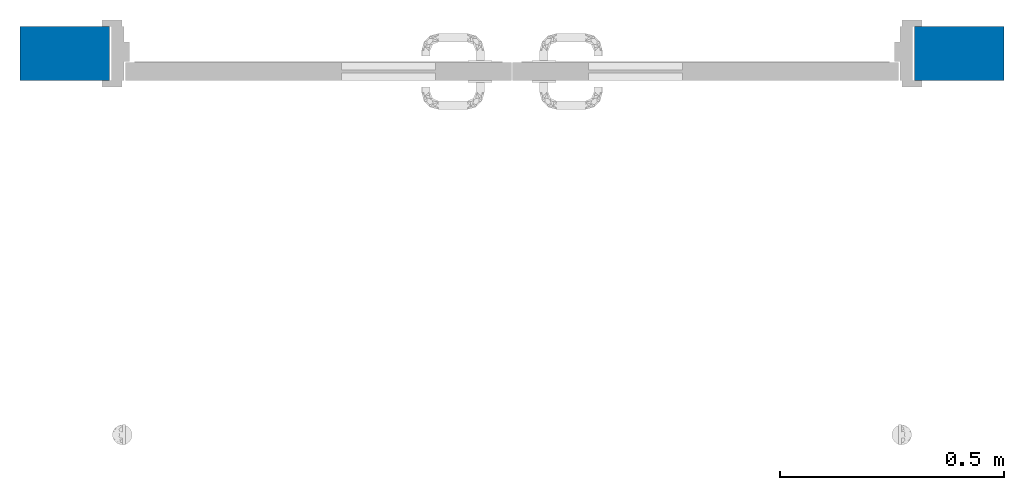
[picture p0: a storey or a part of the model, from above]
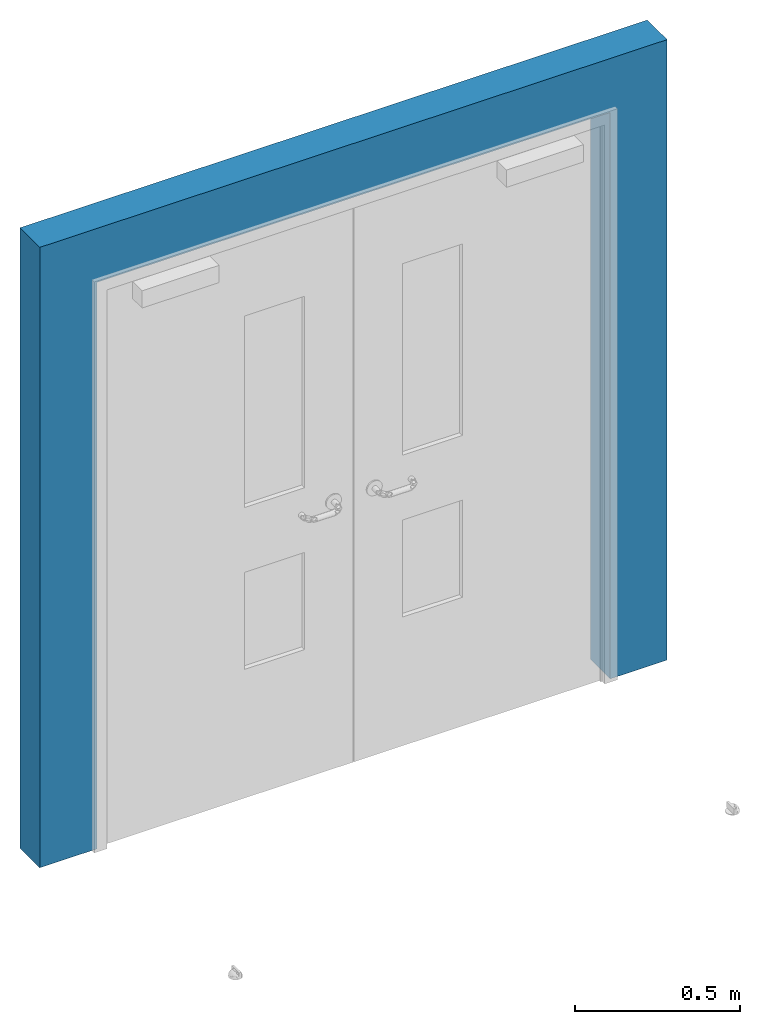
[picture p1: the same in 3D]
Properties of the parts of a building model (IFC2X3)

# File
Description: ViewDefinition [CoordinationView_V2.0]
File name: Project Number
Time: 2014-12-09T12:13:59
Written by: The EXPRESS Data Manager Version 5.01.0100.02.64mod : 6 Jun 2012
Made in: 20130709_2115(x64) - Exporter 3.12.0.0 - Alternate UI 2.12.0.0
Comment: STEP Physical File produced by: The EXPRESS Data Manager Version 5.01.0100.02.64mod : 6 Jun 2012 * Module: EDMstepFileFactory/EDMstandAlone * Creation date: Tue Dec 09 12:13:59 2014 * Host: NCL-PI08 * Database: C:\Users\KovacsG\AppData\Local\Temp\{104F14B4-FB82-4425-A065-D12D6DB6A748}\ifc * Database version: 5507 * Database creation date: Tue Dec 09 12:13:59 2014 * Schema: IFC2X3 * Model: DataRepository.ifc * Model creation date: Tue Dec 09 12:13:59 2014 * Header model: DataRepository.ifc_HeaderModel * Header model creation date: Tue Dec 09 12:13:59 2014 * EDMuser: sdai-user * EDMgroup: sdai-group * License ID and type: 5605 : Permanent license. Expiry date: * EDMstepFileFactory options: 020000

# IfcProject, Project Number
LongName: Project Name; Phase: Project Status

# IfcSite, Default
RefLatitude: 51, 30, 0, 549316; RefLongitude: 0, -7, -34, -450321; RefElevation: 0 mm

# IfcBuildingStorey, Level 0
LongName: Level 0; Elevation: 0 mm

# IfcDoor: 1800x2100mm-NFR, NBS_AssaAbloyLtd_DrsetSym_SelectDoorSix:1800x2100mm-NFR:410865
In: Level 0
Type - ParameterTakesPrecedence: no; Sizeable: no; Material: NBS_Concept, NBS_Glass
OverallHeight: 2100 mm; OverallWidth: 1800 mm
NBS_General - Author: NBS; BIMObjectName: NBS_AssaAbloyLtd_DoorsetSystem_SelectDoorSix_1800x2100mm-NFR; ManufacturerURL: www.assaabloy.co.uk; NBSCertification: www.nationalbimlibrary.com/assa-abloy/assa-abloy-select-door-six; NBSDescription: Doorset system; NBSNote: n/a; NBSOfficeMasterTag: n/a; NBSReference: 25-50-20/120; NBSTypeID: n/a; ProductInformation: n/a; Revision: n/a; Uniclass2: 25-30-20/120; Version: 2
COBie - AccessibilityPerformance: n/a; AssetIdentifier: n/a; AssetType: Fixed; BarCode: n/a; Category: n/a; CodePerformance: n/a; Color: n/a; Constituents: n/a; Description: ASSA ABLOY Double Doorset designed for use in an education or health environment such as a typical corridor application; DurationUnit: year; ExpectedLife: n/a; Features: n/a; Finish: n/a; Grade: n/a; InstallationDate: 1900-12-31T23:59:59; Manufacturer: ASSA ABLOY LTD; Material: n/a; ModelNumber: n/a; ModelReference: ASSA ABLOY Select Door Six; Name: Doorset system; NominalHeight: 2100 mm; NominalLength: 0 mm; NominalWidth: 1800 mm; ReplacementCost: n/a; SerialNumber: n/a; Shape: Rectangle; Size: 1800 x 2100 mm; SustainabilityPerformance: n/a; TagNumber: n/a; WarrantyDescription: n/a; WarrantyDurationLabor: n/a; WarrantyDurationParts: n/a; WarrantyDurationUnit: year; WarrantyGuarantorLabor: n/a; WarrantyGuarantorParts: n/a; WarrantyStartDate: 1900-12-31T23:59:59
Pset_DoorCommon - Reference: n/a; FireRating: Unrated; AcousticRating: 30 dB; SecurityRating: n/a; IsExternal: no; Infiltration: 0 m3/s; ThermalTransmittance: 0 kg/K/s3; HandicapAccessible: no; FireExit: no; SelfClosing: no; SmokeStop: no; HasDrive: no
NBS_Data - AccessoryOptions: ScanFlex Signage (male symbol, female symbol, disabled symbol, fire door keep shut, automatic fire door keep clear); AcousticRatingOptions: 30 dB (40 mm doorset thickness), 35 dB (62 mm doorset thickness); AdditionalHardware: DC500A CAM-motion; AirTransferGrille: no; AirTransferGrilleSize: n/a; AlternativeDoorsetGlazing: n/a; AntiFingerTrapRequirement: no; AutomaticHardware: n/a; BreakoutFacility: no; CloserOptions: DC500A CAM-motion, DC700A CAM-motion, DC840A Concealed CAM-motion, DC860A Concealed CAM-motion, 4200 Floor Spring. Hold open option available on all closers; ComponentNumber: n/a; Configuration: Double leaf, single action; DoorNumber: n/a; DoorSeal: no; DoorsetFasteners: n/a; DoorsetType: Timber; DoorstopOptions: ScanFlex 95 45 07 or 95 45 06 floor door stop, ScanFlex 95 45 08 or 95 45 45 wall door stop; Durability: High; ElectronicLock: no; EmergencyPanicOperation: n/a; FireRatingOptions: Unrated (40 mm doorset thickness), 30 minutes (40 mm doorset thickness), 60 minutes (54 mm doorset thickness); FloorFinish: n/a; FrameFinish: n/a; FrameMaterial: n/a; FrameProfile: n/a; FrameRevealFiller: n/a; FrameSeal: no; FrameWidthOptions: 100 mm, 122 mm; GlassThicknessOptions: 6 mm clear toughened (non fire), 11 mm clear Contraflam Lite (all fire rated), 12 mm Stadlip (all acoustic); GlassType: Non fire; Handing: n/a; Hanging: 3228 hinge; HardwareSet: ASSA; HeadDetail: n/a; HingeOptions: 3228 hinge; HoldOpen: no; JambDetail: n/a; KeySuiting: n/a; LeafEdgings: n/a; LeafFacing: Hardwood Veneer; LeafFacingOptions: 6 veneers or 120 laminate colours; LeafSwing: n/a; LeverHandleOptions: Pull Handle, ScanFlex 95 44 95 Nordic U lever handle; LockcaseOptions: Please refer to technical literature for available options; OpeningMechanism: no; Operating: ScanFlex 95 44 95 Nordic U lever handle; OverPanels: n/a; PlatesAndStops: 95 45 06 ScanFlex floor door stop, Kick Plate (min. 200 mm high); Securing: Assa Modular lock, P600 cylinder; SidePanels: n/a; SignageFire: n/a; SignageSecurity: n/a; SignageWayfinding: n/a; StructuralOpeningOptions: 1500 x 2100 mm, 1600 x 2100 mm, 1700 x 2100 mm, 1800 x 2100 mm, 1900 x 2100 mm, 2000 x 2100 mm; SuitableEnvironment: Education/health; SuitableLocation: Corridor; SystemAccessories: n/a; ThresholdBase: n/a; ThresholdRequired: no; ThresholdStripping: no; Trim: n/a; VisionPanelConfiguration: Type 13; VisionPanelOptions: Type 13 (250 x 750 mm & 250 x 400 mm), Type 14 (205 x 1250 mm)

# IfcWallStandardCase: Basic Wall:Int - 120 - Brick, Basic Wall:Int - 120 - Brick:410822
In: Level 0
Type - PredefinedType: STANDARD; Material: Brick, Common 120 mm
